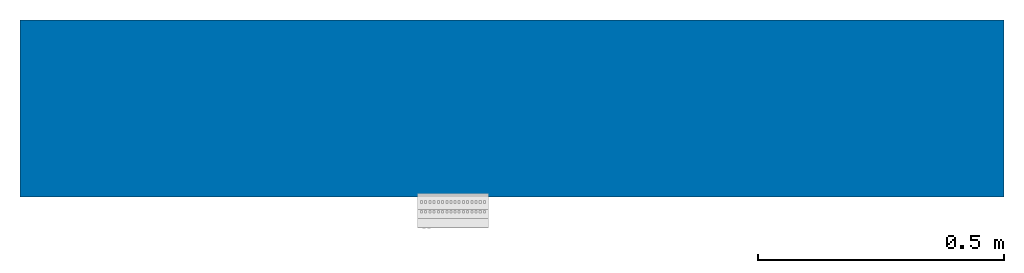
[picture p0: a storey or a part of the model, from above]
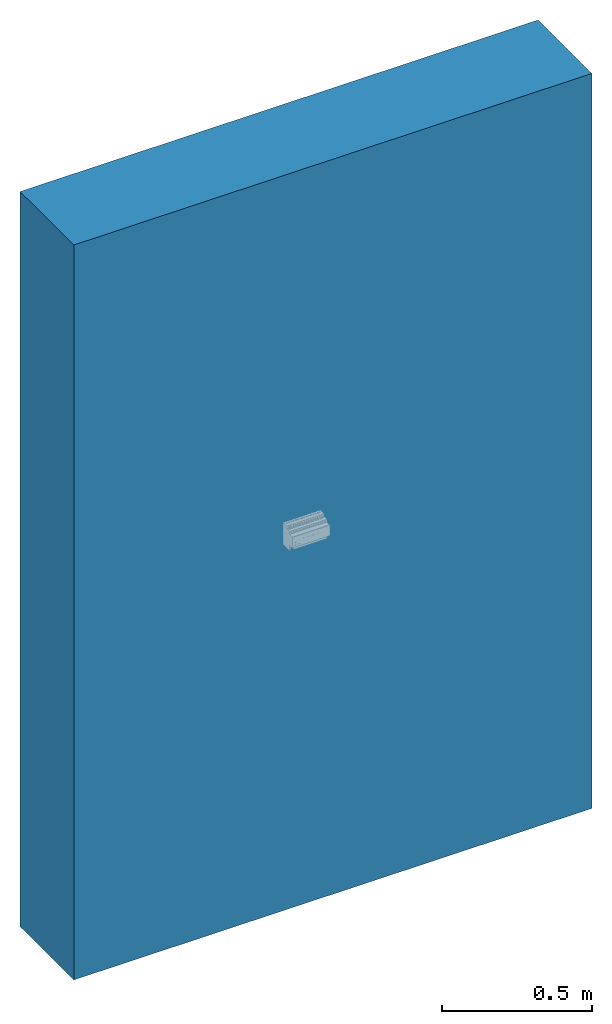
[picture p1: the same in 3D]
Properties of the parts of a building model (IFC2X3)

# File
Description: ViewDefinition [CoordinationView_V2.0]
File name: Projektnummer
Time: 2019-08-29T11:59:39
Written by: The EXPRESS Data Manager Version 5.02.0100.07 : 28 Aug 2013
Made in: 20160225_1515(x64) - Exporter 17.0.416.0 - Alternate UI 17.12.14.0
Comment: STEP Physical File produced by: The EXPRESS Data Manager Version 5.02.0100.07 : 28 Aug 2013 * Module: EDMstepFileFactory/EDMstandAlone * Creation date: Thu Aug 29 11:59:39 2019 * Host: B-BIM-NB-4736 * Database: C:\Users\Enkler\AppData\Local\Temp\{1DA7931D-1BC7-469D-8BEB-876356C423B5}\ifc * Database version: 5507 * Database creation date: Thu Aug 29 11:59:38 2019 * Schema: IFC2X3 * Model: DataRepository.ifc * Model creation date: Thu Aug 29 11:59:38 2019 * Header model: DataRepository.ifc_HeaderModel * Header model creation date: Thu Aug 29 11:59:38 2019 * EDMuser: sdai-user * EDMgroup: sdai-group * License ID and type: 5605 : Permanent license. Expiry date: * EDMstepFileFactory options: 020000

# IfcProject, Projektnummer
LongName: Projektname; Phase: Projektstatus

# IfcSite, Default
RefLatitude: 52, 30, 59, 765625; RefLongitude: 13, 23, 59, 998626; RefElevation: 0 m
Sonstige - Kategorie: Projektinformationen; Kundenname: Bauherr; Projektadresse: Projektadresse; Projektausgabedatum: Projekt Datum; Projektname: Projektname; Projektnummer: Projektnummer; Projektstatus: Projektstatus; Verfasser eMail: E-Mail; Verfasser Firma 1: Firma 1; Verfasser Firma 2: Firma 2; Verfasser PLZ Ort: PLZ Ort; Verfasser Strasse: Strasse; Verfasser Telefax: Telefax; Verfasser Telefon: Telefon

# IfcBuilding
Pset_BuildingCommon - NumberOfStoreys: 1
Sonstige - Kategorie: Projektinformationen; Kundenname: Bauherr; Projektadresse: Projektadresse; Projektausgabedatum: Projekt Datum; Projektname: Projektname; Projektnummer: Projektnummer; Projektstatus: Projektstatus; Verfasser eMail: E-Mail; Verfasser Firma 1: Firma 1; Verfasser Firma 2: Firma 2; Verfasser PLZ Ort: PLZ Ort; Verfasser Strasse: Strasse; Verfasser Telefax: Telefax; Verfasser Telefon: Telefon

# IfcBuildingStorey, Ebene 0
LongName: Ebene 0; Elevation: 0 m
Sonstige - Kategorie: Ebenen; Familienname: Ebene; Familie: Ebene: Ebene; Familie und Typ: Ebene: Ebene; Typ: Ebene: Ebene; Typ-ID: Ebene: Ebene
ID-Daten - Typname: Ebene; Tragwerk: no; Gebäudegeschoss: yes; Name: Ebene 0
Grafiken - Farbe: 16711680; Linienmuster: Verdeckt; Linienstärke: 1; Symbol: Beschriftung Ebene: Beschriftung Ebene; Symbol bei Ende 1 Standard: no; Symbol bei Ende 2 Standard: yes
Abhängigkeiten - Basishöhe: Projekt-Basispunkt; Ansicht: 0 m
Abmessungen - Höhe für Berechnung: 0 m

# IfcBuildingElementProxy: GIRA_103800_ENG, GIRA_103800_ENG:GIRA_103800_ENG:389822
In: Ebene 0
Type - Material: White
Type - Abhängigkeiten - Vorgabe-Ansicht: 1.2192 m
Type - Allgemein - Bus system KNX YesNo: yes; Bus system LON YesNo: no; Bus system Powernet YesNo: no; Bus system radio frequent YesNo: no; Degree of protection (IP) Text: IP20; HeinzeBIM: https://www.heinze.de/bim/swit-blind-act-16-g-8-g-16-a-man-act-knx-dra/8ebf279c5e881561596a9ddc5a0fea9d1c500635; Local operation/hand operation YesNo: yes; Mounting method Text: DRA (DIN-rail adapter)
Type - ID-Daten - Beschreibung: Sw. blind act.16g 8g 16A DRA KNX,KNX switching actuator, 16-gang 16 A blind actuator, 8-gang 16 A with manual actuation,,DRA plus,Depending on the parameterisation, the actuator can be used as a switching actuator or a blind actuator. Mixed configurations of switching and blind actuators are also possible. For the blind actuator function, two neighbouring relay outputs are combined to form one blind output.,,Features:,- Switching status indication for each relay.,- Manual actuation for changing over the relays in parallel or without KNX operation.,- Central switch-off possible per manual actuation.,- With integrated bus coupler.,- Different external conductors may be connected to the outputs.,- Behaviour after bus voltage failure and recovery can be set.,- Feedback can be delayed until after the recovery of bus voltage.,- Integration in scenes is possible, 8 internal scenes at the most can be parameterised per channel.,- Memory function for light scenes.,- Building site operation: Outputs can be operated manually without bus voltage with operating voltage only.,Blind functions:,- Separately parameterisable movement times with movement time extension for moving into the upper end position.,- Central control of all blind outputs possible.,- Feedback of the curtain position or slat position.,- Assignments of up to five different safety functions (three wind alarms, one rain alarm, one frost alarm) or optionally with cyclical monitoring.,- Forced setting function can be realised for each blind output.,- Sun protection function with fixed and variable curtain or slat positions can be activated.,Switching functions:,- NO contact or NC contact operation can be set.,- Behaviour after bus voltage failure and recovery can be set.,- Central switching function.,- Group feedback for reduction of bus load.,- Active or passive (object can be read out) cyclical feedback function.,- Logical linking function for each output.,- Block function can be parameterised for each channel. As an alternative, forced setting function for each output.,- Time functions (switch-on off delay, staircase light function – also with advance warning function).,- Independent control of up to eight blind outputs.,- Independent switching of up to 16 switching outputs.,,Notes :,- Installation on DIN top-hat rail.,- VDE approval in accordance with EN 60669-1, EN 60669-2-1.; GTIN: 4010337042204; HAN: 103800; Hersteller: Gira; Typname: Swit./blind act. 16-g/8-g 16 A man.act. KNX DRA; URL: https://www.gira.de/
Type - Sonstige - Kategorie: Elektroinstallationen; Familienname: GIRA_103800_ENG
Pset_BuildingElementProxyCommon - Reference: GIRA_103800_ENG
Pset_ManufacturerTypeInformation - Manufacturer: Gira
Abhängigkeiten - Basisbauteil: Basiswand : MW 24.0 WD 12.0; Ebene: Ebene: Ebene 0; Erhebung: 1.54007 m
Abmessungen - Fläche: 0.029516 m2; Volumen: 0.000917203 m3
ID-Daten - Kennzeichen: 1
Phasen - Phase erstellt: Phase 1
Sonstige - Bauteillistenebene: Ebene: Ebene 0; Familie: GIRA_103800_ENG: GIRA_103800_ENG; Familie und Typ: GIRA_103800_ENG: GIRA_103800_ENG; Typ: GIRA_103800_ENG: GIRA_103800_ENG; Typ-ID: GIRA_103800_ENG: GIRA_103800_ENG

# IfcWallStandardCase: Basiswand:MW 24.0 WD 12.0, Basiswand:MW 24.0 WD 12.0:388644
In: Ebene 0
Type - PredefinedType: STANDARD; Material: Wärmedämmung - hart 0.12 m, Mauerwerk - Ziegel, verputzt 0.24 m
Type - Analytische Eigenschaften - Absorptionsgrad: 0.7; Rauigkeit: 3; Thermischer Widerstand (R): 3.87302; Thermisch wirksame Masse: 316537; Wärmeübergangskoeffizient (U): 0.258197
Type - Grafiken - Farbfüllung für groben Maßstab: 0; Füllmuster für groben Maßstab: Standard - Füllung
Type - ID-Daten - Beschreibung: Mauerwerk 24.0 cm, Wärmedämmung 12.0 cm; Typenkommentare: Mehrschaliges Mauerwerk; Typname: MW 24.0 WD 12.0
Type - Konstruktion - Abschluss an Öffnungen: Keine; Abschluss an Wänden: Keine; Breite: 0.36 m; Funktion: Außen
Type - Materialien und Oberflächen - Tragendes Material: Mauerwerk - Ziegel, verputzt
Type - Sonstige - Kategorie: Wände; Familienname: Basiswand
Abhängigkeiten - Abhängigkeit oben: Ebene: Ebene 1; Abhängigkeit unten: Ebene: Ebene 0; Basislinie: Wandachse; Für Körper: no; Nicht verknüpfte Höhe: 3 m; Oberkante ist fixiert.: no; Raumbegrenzung: yes; Unterkante ist fixiert: no; Verlängerungsabstand oben: 0 m; Verlängerungsabstand unten: 0 m; Versatz oben: 0 m; Versatz unten: 0 m
Abmessungen - Fläche: 6 m2; Länge: 2 m; Volumen: 2.16 m3
Phasen - Phase erstellt: Phase 1
Sonstige - Familie: Basiswand: MW 24.0 WD 12.0; Familie und Typ: Basiswand: MW 24.0 WD 12.0; Typ: Basiswand: MW 24.0 WD 12.0; Typ-ID: Basiswand: MW 24.0 WD 12.0
Tragwerk - Berechnungsmodell aktivieren: no; Tragwerk: no; Tragwerksverwendung: Nichttragend
Pset_WallCommon - Reference: MW 24.0 WD 12.0; LoadBearing: no; ExtendToStructure: no; IsExternal: yes; ThermalTransmittance: 0.258197 kg/K/s3
